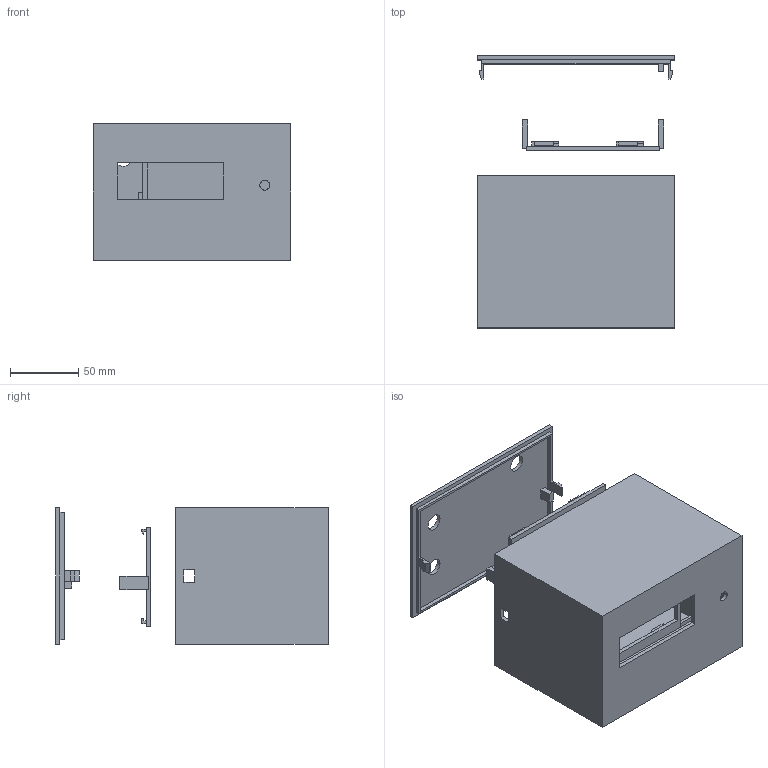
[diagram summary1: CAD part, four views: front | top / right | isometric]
STEP (ISO 10303-21) file: header records copied from the file, then geometry measured from it (millimetres).
FILE_DESCRIPTION(('Open CASCADE Model'),'2;1');
FILE_NAME('Open CASCADE Shape Model','2026-11-04T18:24:56',('Author'),( 'Open CASCADE'),'Open CASCADE STEP processor 7.8','Open CASCADE 7.8' ,'Unknown');
FILE_SCHEMA(('AUTOMOTIVE_DESIGN { 1 0 10303 214 1 1 1 1 }'));
Length unit declared in the file: millimetre
Products named in the file (4): Boitier_3_pieces_vue_eclatee; 01_Coque_supports_et_clips_integres; 02_Berceau_B_et_clips_integres; 03_Panneau_arriere_et_clips_integres
Assembly tree (3 placements, depth 2):
  Boitier_3_pieces_vue_eclatee
    01_Coque_supports_et_clips_integres
    02_Berceau_B_et_clips_integres
    03_Panneau_arriere_et_clips_integres
Bounding box: 145 x 200 x 100 mm (x, y, z)
Volume: 268212.9 mm3; surface area: 195177.4 mm2
Topology: 3 solids, 3 shells, 268 faces, 726 edges, 482 vertices
Faces by surface type: plane 264, cylinder 4
Full cylindrical faces by diameter (mm): 7.2 x1, 12.4 x1, 12.5 x2
Entity records: 17839 total; most frequent: CARTESIAN_POINT 2932, DIRECTION 2730, LINE 2162, VECTOR 2162, ORIENTED_EDGE 1452, PCURVE 1452, DEFINITIONAL_REPRESENTATION 1452, EDGE_CURVE 726
